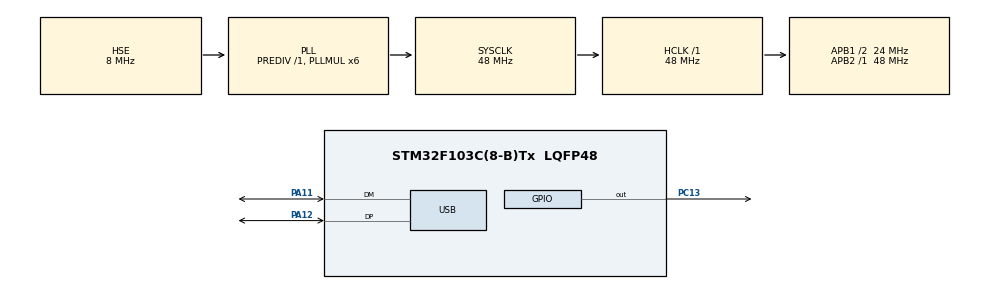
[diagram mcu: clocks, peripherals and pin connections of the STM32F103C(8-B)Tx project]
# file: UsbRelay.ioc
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Mcu.Family=STM32F1
Mcu.Name=STM32F103C(8-B)Tx
Mcu.Package=LQFP48
NVIC.PriorityGroup=NVIC_PRIORITYGROUP_4
NVIC.USB_LP_CAN1_RX0_IRQn=true\:0\:0\:false\:false\:true\:false\:true
PA11.Mode=Device
PA11.Signal=USB_DM
PA12.Mode=Device
PA12.Signal=USB_DP
PA13.Mode=Serial_Wire
PA13.Signal=SYS_JTMS-SWDIO
PA14.Mode=Serial_Wire
PA14.Signal=SYS_JTCK-SWCLK
PC13-TAMPER-RTC.GPIO_ModeDefaultOutputPP=GPIO_MODE_OUTPUT_OD
PC13-TAMPER-RTC.PinState=GPIO_PIN_SET
PC13-TAMPER-RTC.Signal=GPIO_Output
PC14-OSC32_IN.Mode=LSE-External-Oscillator
PC14-OSC32_IN.Signal=RCC_OSC32_IN
PC15-OSC32_OUT.Mode=LSE-External-Oscillator
PC15-OSC32_OUT.Signal=RCC_OSC32_OUT
PD0-OSC_IN.Mode=HSE-External-Oscillator
PD0-OSC_IN.Signal=RCC_OSC_IN
PD1-OSC_OUT.Mode=HSE-External-Oscillator
PD1-OSC_OUT.Signal=RCC_OSC_OUT
ProjectManager.HeapSize=0x200
ProjectManager.StackSize=0x400
ProjectManager.TargetToolchain=MDK-ARM V5.27
RCC.AHBFreq_Value=48000000
RCC.APB1CLKDivider=RCC_HCLK_DIV2
RCC.APB1Freq_Value=24000000
RCC.APB1TimFreq_Value=48000000
RCC.APB2Freq_Value=48000000
RCC.APB2TimFreq_Value=48000000
RCC.HCLKFreq_Value=48000000
RCC.PLLMUL=RCC_PLL_MUL6
RCC.SYSCLKFreq_VALUE=48000000
RCC.SYSCLKSource=RCC_SYSCLKSOURCE_PLLCLK
RCC.USBFreq_Value=48000000
USB_DEVICE.CLASS_NAME_FS=CDC
USB_DEVICE.USBD_MAX_STR_DESC_SIZ=256
USB_DEVICE.VirtualMode=Cdc
USB_DEVICE.VirtualModeFS=Cdc_FS
VP_USB_DEVICE_VS_USB_DEVICE_CDC_FS.Mode=CDC_FS
board=custom

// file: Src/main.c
/* USER CODE BEGIN Header */
/**
  ******************************************************************************
  * @file           : main.c
  * @brief          : Main program body
  ******************************************************************************
  * @attention
  *
  * <h2><center>&copy; Copyright (c) 2020 STMicroelectronics.
  * All rights reserved.</center></h2>
  *
  * This software component is licensed by ST under Ultimate Liberty license
  * SLA0044, the "License"; You may not use this file except in compliance with
  * the License. You may obtain a copy of the License at:
  *                             www.st.com/SLA0044
  *
  ******************************************************************************
  */
/* USER CODE END Header */

#include "main.h"
#include "usb_device.h"
#include "usbd_cdc_if.h"
#include "16S2.h"

/* USER CODE BEGIN PD */
#define ADC_K  360/4096
#define Relay0	0
#define Relay1	1
#define Relay2	2
#define Relay3	3
#define Relay4	4
#define Relay5	5
#define Relay6	6
#define Relay7	7

/* USER CODE END PD */

void SystemClock_Config(void);
static void MX_GPIO_Init(void);

uint8_t ComDataReceive[256];
uint8_t ComDataToSend[256];
uint16_t AdcBuf[4];
uint8_t string[16];
uint8_t RelayState;
int main(void)
{

  /* MCU Configuration--------------------------------------------------------*/

  /* Reset of all peripherals, Initializes the Flash interface and the Systick. */
  HAL_Init();

  /* Configure the system clock */
  SystemClock_Config();

  /* Initialize all configured peripherals */
  MX_GPIO_Init();
  MX_USB_DEVICE_Init();

  /* Infinite loop */
  while (1)
  {
		//ComDataToSend[0] = RelayState;
		//CDC_Transmit_FS(ComDataToSend, 8);
		//memset(ComDataToSend,0,256);
		HAL_Delay(100);

		if(ComDataReceive[0] == '1') {
				if(ComDataReceive[1] == 'Y') {
					HAL_GPIO_WritePin(GPIOB, GPIO_PIN_8, GPIO_PIN_RESET);
					ComDataToSend[0] = 'Y';
					CDC_Transmit_FS(ComDataToSend, 2);
				}
				else if(ComDataReceive[1] == 'N') {
					HAL_GPIO_WritePin(GPIOB, GPIO_PIN_8, GPIO_PIN_SET);
					ComDataToSend[0] = 'N';
					CDC_Transmit_FS(ComDataToSend, 2);
				}
			}

		if(ComDataReceive[0] == '2') {
				if(ComDataReceive[1] == 'Y') {
					HAL_GPIO_WritePin(GPIOB, GPIO_PIN_9, GPIO_PIN_RESET);
					ComDataToSend[1] = 'Y';
					CDC_Transmit_FS(ComDataToSend, 2);
				}
				else if(ComDataReceive[1] == 'N') {
					HAL_GPIO_WritePin(GPIOB, GPIO_PIN_9, GPIO_PIN_SET);
					ComDataToSend[1] = 'N';
					CDC_Transmit_FS(ComDataToSend, 2);
				}
			}

    //
  }
}

void SystemClock_Config(void)
{
  RCC_OscInitTypeDef RCC_OscInitStruct = {0};
  RCC_ClkInitTypeDef RCC_ClkInitStruct = {0};
  RCC_PeriphCLKInitTypeDef PeriphClkInit = {0};

  /** Initializes the CPU, AHB and APB busses clocks
  */
  RCC_OscInitStruct.OscillatorType = RCC_OSCILLATORTYPE_HSE;
  RCC_OscInitStruct.HSEState = RCC_HSE_ON;
  RCC_OscInitStruct.HSEPredivValue = RCC_HSE_PREDIV_DIV1;
  RCC_OscInitStruct.HSIState = RCC_HSI_ON;
  RCC_OscInitStruct.PLL.PLLState = RCC_PLL_ON;
  RCC_OscInitStruct.PLL.PLLSource = RCC_PLLSOURCE_HSE;
  RCC_OscInitStruct.PLL.PLLMUL = RCC_PLL_MUL6;
  if (HAL_RCC_OscConfig(&RCC_OscInitStruct) != HAL_OK)
  {
    Error_Handler();
  }
  /** Initializes the CPU, AHB and APB busses clocks
  */
  RCC_ClkInitStruct.ClockType = RCC_CLOCKTYPE_HCLK|RCC_CLOCKTYPE_SYSCLK
                              |RCC_CLOCKTYPE_PCLK1|RCC_CLOCKTYPE_PCLK2;
  RCC_ClkInitStruct.SYSCLKSource = RCC_SYSCLKSOURCE_PLLCLK;
  RCC_ClkInitStruct.AHBCLKDivider = RCC_SYSCLK_DIV1;
  RCC_ClkInitStruct.APB1CLKDivider = RCC_HCLK_DIV2;
  RCC_ClkInitStruct.APB2CLKDivider = RCC_HCLK_DIV1;

  if (HAL_RCC_ClockConfig(&RCC_ClkInitStruct, FLASH_LATENCY_1) != HAL_OK)
  {
    Error_Handler();
  }
  PeriphClkInit.PeriphClockSelection = RCC_PERIPHCLK_USB;
  PeriphClkInit.UsbClockSelection = RCC_USBCLKSOURCE_PLL;
  if (HAL_RCCEx_PeriphCLKConfig(&PeriphClkInit) != HAL_OK)
  {
    Error_Handler();
  }
}

static void MX_GPIO_Init(void)
{
  GPIO_InitTypeDef GPIO_InitStruct = {0};

  /* GPIO Ports Clock Enable */
	__HAL_RCC_GPIOA_CLK_ENABLE();
  __HAL_RCC_GPIOB_CLK_ENABLE();
	__HAL_RCC_GPIOC_CLK_ENABLE();

  /*Configure GPIO pin : PB9, PB9 */
  GPIO_InitStruct.Pin = GPIO_PIN_8 | GPIO_PIN_9;
  GPIO_InitStruct.Mode = GPIO_MODE_OUTPUT_OD;
  GPIO_InitStruct.Pull = GPIO_NOPULL;
  GPIO_InitStruct.Speed = GPIO_SPEED_FREQ_LOW;
  HAL_GPIO_Init(GPIOB, &GPIO_InitStruct);
	/*Configure GPIO pin Output Level */
	HAL_GPIO_WritePin(GPIOB, GPIO_PIN_8, GPIO_PIN_SET);
	HAL_GPIO_WritePin(GPIOB, GPIO_PIN_9, GPIO_PIN_SET);
}

/* USER CODE END 4 */

void Error_Handler(void)
{
}

/************************ (C) COPYRIGHT STMicroelectronics *****END OF FILE****/
